VERSION 5.7 ;
  NOWIREEXTENSIONATPIN ON ;
  DIVIDERCHAR "/" ;
  BUSBITCHARS "[]" ;
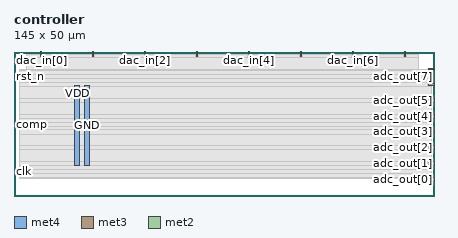
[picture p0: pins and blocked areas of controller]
MACRO controller
  CLASS BLOCK ;
  FOREIGN controller ;
  ORIGIN 0.000 0.000 ;
  SIZE 145.000 BY 50.000 ;
  PIN GND
    DIRECTION INOUT ;
    USE GROUND ;
    PORT
      LAYER met4 ;
        RECT 24.340 10.640 25.940 38.320 ;
    END
  END GND
  PIN VDD
    DIRECTION INOUT ;
    USE POWER ;
    PORT
      LAYER met4 ;
        RECT 21.040 10.640 22.640 38.320 ;
    END
  END VDD
  PIN adc_out[0]
    DIRECTION OUTPUT ;
    USE SIGNAL ;
    ANTENNADIFFAREA 0.445500 ;
    PORT
      LAYER met3 ;
        RECT 143.000 5.480 145.000 6.080 ;
    END
  END adc_out[0]
  PIN adc_out[1]
    DIRECTION OUTPUT ;
    USE SIGNAL ;
    ANTENNADIFFAREA 0.445500 ;
    PORT
      LAYER met3 ;
        RECT 143.000 10.920 145.000 11.520 ;
    END
  END adc_out[1]
  PIN adc_out[2]
    DIRECTION OUTPUT ;
    USE SIGNAL ;
    ANTENNADIFFAREA 0.445500 ;
    PORT
      LAYER met3 ;
        RECT 143.000 16.360 145.000 16.960 ;
    END
  END adc_out[2]
  PIN adc_out[3]
    DIRECTION OUTPUT ;
    USE SIGNAL ;
    ANTENNADIFFAREA 0.445500 ;
    PORT
      LAYER met3 ;
        RECT 143.000 21.800 145.000 22.400 ;
    END
  END adc_out[3]
  PIN adc_out[4]
    DIRECTION OUTPUT ;
    USE SIGNAL ;
    ANTENNADIFFAREA 0.445500 ;
    PORT
      LAYER met3 ;
        RECT 143.000 27.240 145.000 27.840 ;
    END
  END adc_out[4]
  PIN adc_out[5]
    DIRECTION OUTPUT ;
    USE SIGNAL ;
    ANTENNADIFFAREA 0.445500 ;
    PORT
      LAYER met3 ;
        RECT 143.000 32.680 145.000 33.280 ;
    END
  END adc_out[5]
  PIN adc_out[6]
    DIRECTION OUTPUT ;
    USE SIGNAL ;
    ANTENNADIFFAREA 0.445500 ;
    PORT
      LAYER met3 ;
        RECT 143.000 38.120 145.000 38.720 ;
    END
  END adc_out[6]
  PIN adc_out[7]
    DIRECTION OUTPUT ;
    USE SIGNAL ;
    ANTENNADIFFAREA 0.445500 ;
    PORT
      LAYER met3 ;
        RECT 143.000 43.560 145.000 44.160 ;
    END
  END adc_out[7]
  PIN clk
    DIRECTION INPUT ;
    USE SIGNAL ;
    ANTENNAGATEAREA 0.852000 ;
    PORT
      LAYER met3 ;
        RECT 0.000 8.200 2.000 8.800 ;
    END
  END clk
  PIN comp
    DIRECTION INPUT ;
    USE SIGNAL ;
    ANTENNAGATEAREA 0.213000 ;
    PORT
      LAYER met3 ;
        RECT 0.000 24.520 2.000 25.120 ;
    END
  END comp
  PIN dac_in[0]
    DIRECTION OUTPUT ;
    USE SIGNAL ;
    ANTENNADIFFAREA 0.445500 ;
    PORT
      LAYER met2 ;
        RECT 9.290 48.000 9.570 50.000 ;
    END
  END dac_in[0]
  PIN dac_in[1]
    DIRECTION OUTPUT ;
    USE SIGNAL ;
    ANTENNADIFFAREA 0.445500 ;
    PORT
      LAYER met2 ;
        RECT 27.230 48.000 27.510 50.000 ;
    END
  END dac_in[1]
  PIN dac_in[2]
    DIRECTION OUTPUT ;
    USE SIGNAL ;
    ANTENNADIFFAREA 0.445500 ;
    PORT
      LAYER met2 ;
        RECT 45.170 48.000 45.450 50.000 ;
    END
  END dac_in[2]
  PIN dac_in[3]
    DIRECTION OUTPUT ;
    USE SIGNAL ;
    ANTENNADIFFAREA 0.445500 ;
    PORT
      LAYER met2 ;
        RECT 63.110 48.000 63.390 50.000 ;
    END
  END dac_in[3]
  PIN dac_in[4]
    DIRECTION OUTPUT ;
    USE SIGNAL ;
    ANTENNADIFFAREA 0.445500 ;
    PORT
      LAYER met2 ;
        RECT 81.050 48.000 81.330 50.000 ;
    END
  END dac_in[4]
  PIN dac_in[5]
    DIRECTION OUTPUT ;
    USE SIGNAL ;
    ANTENNADIFFAREA 0.445500 ;
    PORT
      LAYER met2 ;
        RECT 98.990 48.000 99.270 50.000 ;
    END
  END dac_in[5]
  PIN dac_in[6]
    DIRECTION OUTPUT ;
    USE SIGNAL ;
    ANTENNADIFFAREA 0.445500 ;
    PORT
      LAYER met2 ;
        RECT 116.930 48.000 117.210 50.000 ;
    END
  END dac_in[6]
  PIN dac_in[7]
    DIRECTION OUTPUT ;
    USE SIGNAL ;
    ANTENNADIFFAREA 0.445500 ;
    PORT
      LAYER met2 ;
        RECT 134.870 48.000 135.150 50.000 ;
    END
  END dac_in[7]
  PIN rst_n
    DIRECTION INPUT ;
    USE SIGNAL ;
    ANTENNAGATEAREA 0.213000 ;
    PORT
      LAYER met3 ;
        RECT 0.000 40.840 2.000 41.440 ;
    END
  END rst_n
  OBS
      LAYER nwell ;
        RECT 5.330 10.795 139.570 38.165 ;
      LAYER li1 ;
        RECT 5.520 10.795 139.380 38.165 ;
      LAYER met1 ;
        RECT 4.210 10.640 139.770 38.320 ;
      LAYER met2 ;
        RECT 4.230 47.720 9.010 48.690 ;
        RECT 9.850 47.720 26.950 48.690 ;
        RECT 27.790 47.720 44.890 48.690 ;
        RECT 45.730 47.720 62.830 48.690 ;
        RECT 63.670 47.720 80.770 48.690 ;
        RECT 81.610 47.720 98.710 48.690 ;
        RECT 99.550 47.720 116.650 48.690 ;
        RECT 117.490 47.720 134.590 48.690 ;
        RECT 135.430 47.720 139.750 48.690 ;
        RECT 4.230 8.315 139.750 47.720 ;
      LAYER met3 ;
        RECT 2.000 43.160 142.600 43.560 ;
        RECT 2.000 41.840 144.130 43.160 ;
        RECT 2.400 40.440 144.130 41.840 ;
        RECT 2.000 39.120 144.130 40.440 ;
        RECT 2.000 37.720 142.600 39.120 ;
        RECT 2.000 33.680 144.130 37.720 ;
        RECT 2.000 32.280 142.600 33.680 ;
        RECT 2.000 28.240 144.130 32.280 ;
        RECT 2.000 26.840 142.600 28.240 ;
        RECT 2.000 25.520 144.130 26.840 ;
        RECT 2.400 24.120 144.130 25.520 ;
        RECT 2.000 22.800 144.130 24.120 ;
        RECT 2.000 21.400 142.600 22.800 ;
        RECT 2.000 17.360 144.130 21.400 ;
        RECT 2.000 15.960 142.600 17.360 ;
        RECT 2.000 11.920 144.130 15.960 ;
        RECT 2.000 10.520 142.600 11.920 ;
        RECT 2.000 9.200 144.130 10.520 ;
        RECT 2.400 7.800 144.130 9.200 ;
        RECT 2.000 6.480 144.130 7.800 ;
        RECT 2.000 6.080 142.600 6.480 ;
  END
END controller
END LIBRARY

